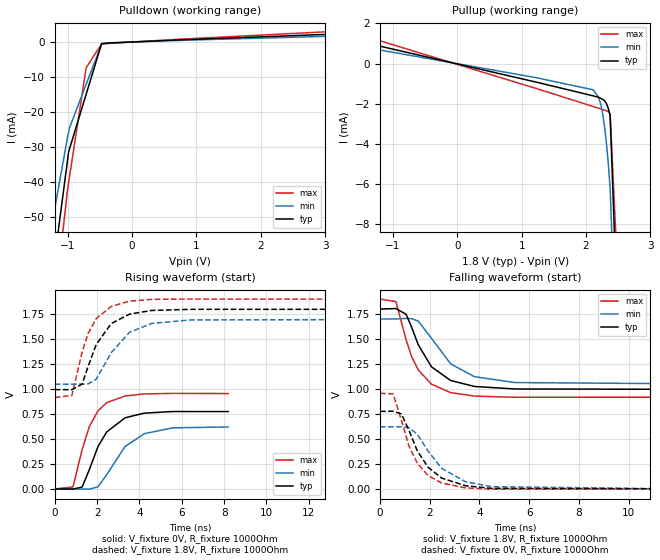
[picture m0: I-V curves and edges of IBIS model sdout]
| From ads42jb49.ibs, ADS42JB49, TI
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|   sdout Model
[Model]   sdout
Model_type   Output
Polarity   Non-Inverting
Vmeas = 0.9
Vref = 1.8
Cref = 2pF
Rref = 2000
|   typ   min   max
|   (nom PVT)   (fast PVT)   (slow PVT)
 C_comp   1.252e-12   1.204e-12   1.298e-12
| Where nom  PVT is Nominal Process, 1.8V, 25C
|   Fast PVT is Strong Process,  1.9V, -40C
|   Slow PVT is Weak Process,   1.7V, 125C
[Voltage Range]   1.8   1.7   1.9
|Junction Temperature
[Temperature Range]   25   125   -40
[Pullup Reference]   1.8   1.7   1.9
[Pulldown Reference]   0   0   0
[Power Clamp Reference]   1.8   1.7   1.9
[GND Clamp Reference]   0   0   0
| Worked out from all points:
|   slope of the pulldown table from 0 to 0.27 V, typ, clamps not added: 1.22 kohm
|   slope of the pullup table from 0 to 0.27 V, typ, clamps not added: 1.33 kohm
|   falling waveform, V_fixture 1.8V, R_fixture 1000Ohm: 20-80 % time 1.11ns typ, 1.34ns min, 925ps max; typ from 1.8 V to 0.996 V
|   rising waveform, V_fixture 0V, R_fixture 1000Ohm: 20-80 % time 1.09ns typ, 1.32ns min, 899ps max; typ from 0 V to 0.775 V
|   rising waveform, V_fixture 1.8V, R_fixture 1000Ohm: 20-80 % time 1.1ns typ, 1.34ns min, 920ps max; typ from 0.995 V to 1.8 V
|   falling waveform, V_fixture 0V, R_fixture 1000Ohm: 20-80 % time 1.08ns typ, 1.29ns min, 908ps max; typ from 0.775 V to 0 V
[Pulldown]
|   Voltage   I(typ)   I(min)   I(max)
-1.8V     -820.6mA   -109.5mA   -1.727A
-1.49V    -102.3mA   -77.5mA    -123.3mA
-1.003V   -34.04mA   -27.36mA   -42.48mA
-984.6mV  -31.42mA   -25.8mA    -40.18mA
-967.3mV  -30.38mA   -24.39mA   -38.1mA
-712.5mV  -14.94mA   -12.12mA   -7.361mA
-472.6mV  -460.4uA   -567.4uA   -540uA
-336.6mV  -280.2uA   -231.3uA   -366.5uA
739.5mV   602.2uA    464.9uA    796uA
3.6V      2.577mA    1.918mA    3.469mA
[Pullup]
|   Voltage   I(typ)   I(min)   I(max)
-1.8V     1.309mA    1.016mA    1.719mA
1.226V    -926.6uA   -706.4uA   -1.243mA
2.113V    -1.613mA   -1.312mA   -2.146mA
2.196V    -1.684mA   -1.696mA   -2.231mA
2.229V    -1.736mA   -2.037mA   -2.264mA
2.259V    -1.788mA   -2.522mA   -2.295mA
2.288V    -1.858mA   -3.157mA   -2.325mA
2.317V    -1.997mA   -3.98mA    -2.357mA
2.344V    -2.227mA   -4.928mA   -2.393mA
2.374V    -2.592mA   -6.201mA   -2.51mA
2.825V    -42.06mA   -45.94mA   -33.2mA
3.6V      -821.5mA   -133.2mA   -867.4mA
[Ramp]
R_load = 1000
|   typ   min   max
dV/dt_r   0.464962/1.08205e-09   0.372481/1.31233e-09   0.573216/8.98731e-10
dV/dt_f   0.482648/1.10643e-09   0.39039/1.33187e-09   0.589514/9.24201e-10
[Falling Waveform]
V_fixture = 1.8V
V_fixture_min = 1.7V
V_fixture_max = 1.9V
R_fixture = 1000Ohm
|   Time   V(typ)   V(min)   V(max)
0s        1.8V       1.7V       1.9V
640ps     1.805V     1.701V     1.875V
1.05ns    1.748V     1.706V     1.493V
1.27ns    1.62V      1.704V     1.326V
1.54ns    1.442V     1.679V     1.191V
2.07ns    1.222V     1.508V     1.048V
2.84ns    1.085V     1.252V     963.5mV
3.8ns     1.025V     1.123V     928.5mV
5.44ns    999.9mV    1.064V     917.2mV
14ns      995.6mV    1.049V     917.5mV
[Rising Waveform]
V_fixture = 0V
V_fixture_min = 0V
V_fixture_max = 0V
R_fixture = 1000Ohm
|   Time   V(typ)   V(min)   V(max)
0s        12.68nV    63.11nV    11.15nV
860ps     -948uV     67.35uV    19.74mV
1.29ns    18.57mV    -738.9uV   392.3mV
1.63ns    191.8mV    -2.055mV   623.1mV
2.04ns    423.5mV    21.38mV    781.8mV
2.45ns    570.2mV    141.8mV    864.2mV
3.32ns    712.7mV    424.7mV    931.4mV
4.23ns    759.6mV    554mV      951.9mV
5.58ns    775.5mV    612.2mV    957.3mV
8.2ns     774.9mV    620.8mV    955.4mV
[Rising Waveform]
V_fixture = 1.8V
V_fixture_min = 1.7V
V_fixture_max = 1.9V
R_fixture = 1000Ohm
|   Time   V(typ)   V(min)   V(max)
0s        995.1mV    1.049V     916mV
810ps     994.7mV    1.049V     937mV
1.29ns    1.05V      1.049V     1.37V
1.58ns    1.23V      1.052V     1.56V
1.96ns    1.448V     1.1V       1.707V
2.67ns    1.657V     1.366V     1.829V
3.53ns    1.751V     1.569V     1.881V
4.58ns    1.788V     1.658V     1.899V
6.39ns    1.799V     1.693V     1.902V
24ns      1.8V       1.7V       1.9V
[Falling Waveform]
V_fixture = 0V
V_fixture_min = 0V
V_fixture_max = 0V
R_fixture = 1000Ohm
|   Time   V(typ)   V(min)   V(max)
0s        775.4mV    620.8mV    956.7mV
530ps     777.5mV    621.3mV    951mV
860ps     750.2mV    622.5mV    687.3mV
1.17ns    583mV      613.2mV    426.4mV
1.5ns     381.2mV    547.6mV    256.7mV
1.93ns    217.2mV    379.7mV    134.6mV
2.48ns    108.1mV    205.3mV    58.32mV
3.45ns    30.66mV    70.31mV    9.384mV
4.5ns     4.733mV    21.87mV    -2.997mV
12ns      12.67nV    63.11nV    11.14nV
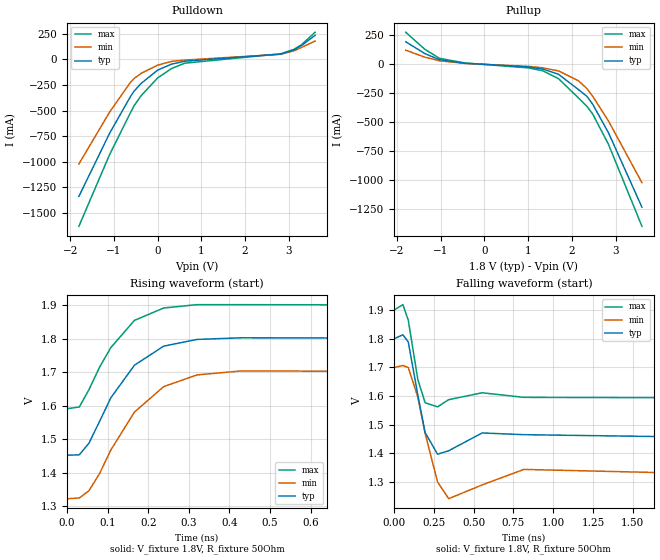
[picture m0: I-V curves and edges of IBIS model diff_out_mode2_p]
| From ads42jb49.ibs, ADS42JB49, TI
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|   diff_out_mode2 Model
[Model]   diff_out_mode2_p
Model_type   Output
Polarity   Non-Inverting
Vmeas = 1.6385
Vref = 1.8
Cref = 0.5pF
Rref = 50
|   typ   min   max
|   (nom PVT)   (fast PVT)   (slow PVT)
C_comp   2.700e-12   2.333e-12   2.765e-12
[Model spec]
|subparameter   typ   min   max
Vmeas   1.6385   1.5288   1.7489
| Where nom  PVT is Nominal Process, 1.8V, 25C
|   Fast PVT is Strong Process,  1.9V, -40C
|   Slow PVT is Weak Process,   1.7V, 125C
[Voltage Range]   1.8   1.7   1.9
|Junction Temperature
[Temperature Range]   25   125   -40
[Pullup Reference]   1.8   1.7   1.9
[Pulldown Reference]   0   0   0
[Power Clamp Reference]   1.8   1.7   1.9
[GND Clamp Reference]   0   0   0
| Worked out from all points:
|   slope of the pulldown table from 0 to 0.27 V, typ, clamps not added: 5.1 ohm
|   slope of the pullup table from 0 to 0.27 V, typ, clamps not added: 49.4 ohm
|   falling waveform, V_fixture 1.8V, R_fixture 50Ohm: 20-80 % time 61.3ps typ, 83.6ps min, 52.9ps max; typ from 1.8 V to 1.45 V
|   rising waveform, V_fixture 1.8V, R_fixture 50Ohm: 20-80 % time 105ps typ, 119ps min, 94.6ps max; typ from 1.45 V to 1.8 V
[Pulldown]
|   Voltage   I(typ)   I(min)   I(max)
-1.8V     -1.338A    -1.021A    -1.63A
-1.096V   -720.2mA   -513.5mA   -928.1mA
-621mV    -362.9mA   -223.5mA   -521mA
-538.2mV  -309.8mA   -186.7mA   -452.7mA
-373.1mV  -233.2mA   -135.2mA   -352.3mA
300uV     -104.8mA   -56.28mA   -180.9mA
316.5mV   -46.52mA   -19.48mA   -89.83mA
621mV     -17.49mA   -6.372mA   -36.72mA
2.819V    52.52mA    50.13mA    54.58mA
3.119V    92.54mA    84.19mA    98.38mA
3.29V     134.9mA    116.7mA    144.1mA
3.6V      235.3mA    179mA      264.9mA
[Pullup]
|   Voltage   I(typ)   I(min)   I(max)
-1.8V     194.6mA    122.1mA    276.8mA
-1.361V   92.3mA     61.21mA    128.8mA
-1.027V   39.25mA    30.36mA    51.49mA
-450mV    9.33mA     7.837mA    11.76mA
1.005V    -22.89mA   -18.07mA   -31.05mA
1.333V    -40.83mA   -30.34mA   -55.62mA
1.694V    -86.52mA   -57.23mA   -124.6mA
2.154V    -219.9mA   -143.9mA   -292.4mA
2.342V    -276.7mA   -210mA     -363.3mA
2.475V    -346mA     -276.7mA   -430.4mA
2.834V    -590.9mA   -489.4mA   -690.6mA
3.6V      -1.235A    -1.023A    -1.4A
[Ramp]
R_load = 50
|   typ   min   max
dV/dt_r   0.0958658/5.93092e-11   0.126182/7.52687e-11  0.0776585/4.97499e-11
dV/dt_f   0.208176/6.1056e-11   0.226063/8.32221e-11   0.184056/5.25283e-11
[Falling Waveform]
V_fixture = 1.8V
V_fixture_min = 1.7V
V_fixture_max = 1.9V
R_fixture = 50Ohm
|   Time   V(typ)   V(min)   V(max)
0s        1.799V     1.699V     1.899V
56ps      1.813V     1.706V     1.918V
90ps      1.788V     1.699V     1.864V
150ps     1.603V     1.596V     1.657V
196ps     1.472V     1.469V     1.576V
274ps     1.397V     1.3V       1.562V
344ps     1.409V     1.242V     1.587V
554ps     1.471V     1.29V      1.611V
816ps     1.465V     1.344V     1.595V
2.498ns   1.452V     1.322V     1.593V
[Rising Waveform]
V_fixture = 1.8V
V_fixture_min = 1.7V
V_fixture_max = 1.9V
R_fixture = 50Ohm
|   Time   V(typ)   V(min)   V(max)
0s        1.452V     1.322V     1.591V
30ps      1.453V     1.324V     1.596V
54ps      1.488V     1.346V     1.648V
80ps      1.553V     1.397V     1.715V
108ps     1.624V     1.468V     1.774V
166ps     1.721V     1.581V     1.855V
238ps     1.778V     1.657V     1.892V
320ps     1.798V     1.692V     1.902V
430ps     1.803V     1.704V     1.902V
1.8ns     1.799V     1.698V     1.899V
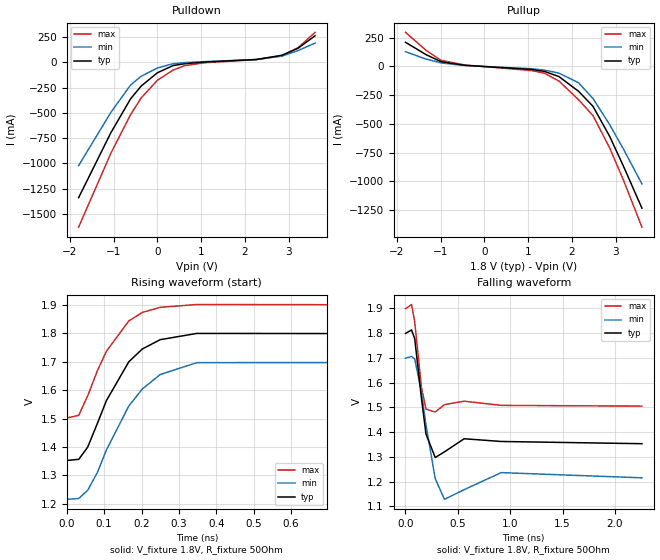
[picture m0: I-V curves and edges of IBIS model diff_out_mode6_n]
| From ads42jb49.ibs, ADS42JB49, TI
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[Model]   diff_out_mode6_n
Model_type   Output
Polarity   Non-Inverting
Vmeas = 1.589
Vref = 1.8
Cref = 0.5pF
Rref = 50
|   typ   min   max
|   (nom PVT)   (fast PVT)   (slow PVT)
C_comp   2.834e-12   2.356e-12   2.851e-12
[Model spec]
|subparameter   typ   min   max
Vmeas   1.589   1.49   1.7074
| Where nom  PVT is Nominal Process, 1.8V, 25C
|   Fast PVT is Strong Process,  1.9V, -40C
|   Slow PVT is Weak Process,   1.7V, 125C
[Voltage Range]   1.8   1.7   1.9
|Junction Temperature
[Temperature Range]   25   125   -40
[Pullup Reference]   1.8   1.7   1.9
[Pulldown Reference]   0   0   0
[Power Clamp Reference]   1.8   1.7   1.9
[GND Clamp Reference]   0   0   0
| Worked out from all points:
|   slope of the pulldown table from 0 to 0.27 V, typ, clamps not added: 4.94 ohm
|   slope of the pullup table from 0 to 0.27 V, typ, clamps not added: 49.4 ohm
|   falling waveform, V_fixture 1.8V, R_fixture 50Ohm: 20-80 % time 67.1ps typ, 95.6ps min, 56.3ps max; typ from 1.8 V to 1.35 V
|   rising waveform, V_fixture 1.8V, R_fixture 50Ohm: 20-80 % time 102ps typ, 118ps min, 91.1ps max; typ from 1.35 V to 1.8 V
[Pulldown]
|   Voltage   I(typ)   I(min)   I(max)
-1.8V     -1.341A    -1.023A    -1.633A
-1.063V   -697.3mA   -495.9mA   -900.2mA
-613.8mV  -362.2mA   -224.7mA   -518.5mA
-373.1mV  -235.8mA   -138.1mA   -353.7mA
20.08fV   -102.9mA   -55.72mA   -177.1mA
358.2mV   -31.82mA   -13.52mA   -76.66mA
621mV     -13.42mA   -2.427mA   -32.54mA
1.082V    3.463mA    7.44mA     -3.434mA
2.252V    27.83mA    28.39mA    27.17mA
2.842V    70.11mA    61.5mA     65.03mA
3.213V    140.7mA    117mA      145.1mA
3.6V      263.4mA    191mA      297.7mA
[Pullup]
|   Voltage   I(typ)   I(min)   I(max)
-1.8V     210.2mA    128.1mA    296.7mA
-1.323V   100.9mA    62.84mA    137.7mA
-986.8mV  40.99mA    30.49mA    52.6mA
-450mV    9.747mA    7.957mA    12.52mA
1.082V    -26.39mA   -20.41mA   -36.01mA
1.374V    -43.31mA   -32.15mA   -58.84mA
1.705V    -88.58mA   -58.29mA   -127.7mA
2.154V    -217mA     -142.8mA   -290.2mA
2.483V    -347.4mA   -279.5mA   -428.4mA
2.865V    -610.5mA   -507.9mA   -710.8mA
3.182V    -871.6mA   -722.3mA   -993.5mA
3.6V      -1.234A    -1.023A    -1.399A
[Ramp]
R_load = 50
|   typ   min   max
dV/dt_r   0.112303/5.91752e-11   0.147577/7.37215e-11  0.0911225/4.77241e-11
dV/dt_f   0.267621/6.70703e-11   0.290297/9.55783e-11   0.236283/5.62373e-11
[Falling Waveform]
V_fixture = 1.8V
V_fixture_min = 1.7V
V_fixture_max = 1.9V
R_fixture = 50Ohm
|   Time   V(typ)   V(min)   V(max)
0s        1.799V     1.699V     1.899V
58ps      1.813V     1.706V     1.916V
88ps      1.778V     1.696V     1.847V
152ps     1.539V     1.564V     1.582V
196ps     1.392V     1.429V     1.493V
284ps     1.297V     1.212V     1.481V
372ps     1.32V      1.128V     1.511V
560ps     1.373V     1.167V     1.525V
914ps     1.362V     1.236V     1.508V
2.258ns   1.353V     1.215V     1.505V
[Rising Waveform]
V_fixture = 1.8V
V_fixture_min = 1.7V
V_fixture_max = 1.9V
R_fixture = 50Ohm
|   Time   V(typ)   V(min)   V(max)
0s        1.352V     1.215V     1.502V
32ps      1.356V     1.218V     1.511V
56ps      1.399V     1.247V     1.58V
82ps      1.483V     1.31V      1.669V
106ps     1.563V     1.389V     1.737V
166ps     1.7V       1.544V     1.844V
202ps     1.745V     1.604V     1.874V
250ps     1.778V     1.655V     1.892V
348ps     1.8V       1.697V     1.902V
2ns       1.798V     1.698V     1.899V
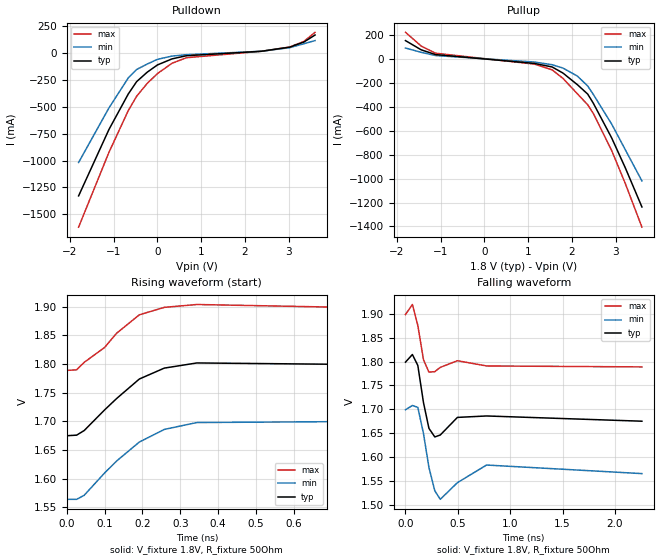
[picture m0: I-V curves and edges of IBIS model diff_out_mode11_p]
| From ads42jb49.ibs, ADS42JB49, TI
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|   diff_out_mode11 Model
[Model]   diff_out_mode11_p
Model_type   Output
Polarity   Non-Inverting
Vmeas = 1.741
Vref = 1.8
Cref = 0.5pF
Rref = 50
|   typ   min   max
|   (nom PVT)   (fast PVT)   (slow PVT)
C_comp   2.464e-12   2.327e-12   2.521e-12
[Model spec]
|subparameter   typ   min   max
Vmeas   1.741   1.641   1.839
| Where nom  PVT is Nominal Process, 1.8V, 25C
|   Fast PVT is Strong Process,  1.9V, -40C
|   Slow PVT is Weak Process,   1.7V, 125C
[Voltage Range]   1.8   1.7   1.9
|Junction Temperature
[Temperature Range]   25   125   -40
[Pullup Reference]   1.8   1.7   1.9
[Pulldown Reference]   0   0   0
[Power Clamp Reference]   1.8   1.7   1.9
[GND Clamp Reference]   0   0   0
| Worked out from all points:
|   slope of the pulldown table from 0 to 0.27 V, typ, clamps not added: 5.59 ohm
|   slope of the pullup table from 0 to 0.27 V, typ, clamps not added: 49.4 ohm
|   falling waveform, V_fixture 1.8V, R_fixture 50Ohm: 20-80 % time 51.5ps typ, 60.1ps min, 48.7ps max; typ from 1.8 V to 1.68 V
|   rising waveform, V_fixture 1.8V, R_fixture 50Ohm: 20-80 % time 127ps typ, 138ps min, 107ps max; typ from 1.68 V to 1.8 V
[Pulldown]
|   Voltage   I(typ)   I(min)   I(max)
-1.8V     -1.329A    -1.018A    -1.62A
-1.107V   -710.9mA   -510.4mA   -923.6mA
-665mV    -380mA     -230.6mA   -534.5mA
-473.4mV  -264.9mA   -152.2mA   -400.9mA
-231.8mV  -177.2mA   -101.6mA   -281.5mA
11.97fV   -110.1mA   -58.1mA    -190.8mA
334.4mV   -53.56mA   -27.52mA   -94.21mA
665mV     -24.29mA   -14.77mA   -42.78mA
2.378V    17.15mA    17.33mA    17.39mA
3.023V    55.88mA    50.66mA    56.97mA
3.344V    103mA      87.29mA    108.9mA
3.6V      168.4mA    116.5mA    193.5mA
[Pullup]
|   Voltage   I(typ)   I(min)   I(max)
-1.8V     156.3mA    94.21mA    225.7mA
-1.44V    78.89mA    58.06mA    110.3mA
-1.113V   39.32mA    31.17mA    50.75mA
1.146V    -34.76mA   -23.05mA   -40.73mA
1.55V     -64.55mA   -45.65mA   -88.85mA
1.797V    -115.5mA   -73.87mA   -160.1mA
2.127V    -213.2mA   -140.9mA   -289.5mA
2.362V    -291.7mA   -224mA     -381.2mA
2.491V    -368.8mA   -295.1mA   -453.9mA
2.909V    -658.6mA   -542.8mA   -764.6mA
3.222V    -910.5mA   -758.8mA   -1.042A
3.6V      -1.237A    -1.019A    -1.406A
[Ramp]
R_load = 50
|   typ   min   max
dV/dt_r   0.044958/9.6857e-11   0.057593/1.11307e-10  0.0363552/8.15696e-11
dV/dt_f   0.0743614/5.14554e-11  0.0808168/6.01146e-11   0.065987/4.7678e-11
[Falling Waveform]
V_fixture = 1.8V
V_fixture_min = 1.7V
V_fixture_max = 1.9V
R_fixture = 50Ohm
|   Time   V(typ)   V(min)   V(max)
0s        1.799V     1.699V     1.899V
66ps      1.815V     1.708V     1.92V
118ps     1.792V     1.704V     1.876V
172ps     1.714V     1.649V     1.804V
224ps     1.66V      1.578V     1.778V
280ps     1.642V     1.529V     1.779V
332ps     1.646V     1.511V     1.788V
496ps     1.683V     1.546V     1.802V
774ps     1.686V     1.583V     1.791V
2.258ns   1.675V     1.565V     1.789V
[Rising Waveform]
V_fixture = 1.8V
V_fixture_min = 1.7V
V_fixture_max = 1.9V
R_fixture = 50Ohm
|   Time   V(typ)   V(min)   V(max)
0s        1.675V     1.564V     1.789V
26ps      1.676V     1.564V     1.79V
46ps      1.684V     1.571V     1.803V
100ps     1.72V      1.61V      1.829V
132ps     1.74V      1.631V     1.854V
192ps     1.774V     1.664V     1.886V
258ps     1.793V     1.686V     1.899V
344ps     1.802V     1.698V     1.904V
816ps     1.799V     1.7V       1.898V
2.012ns   1.799V     1.699V     1.899V
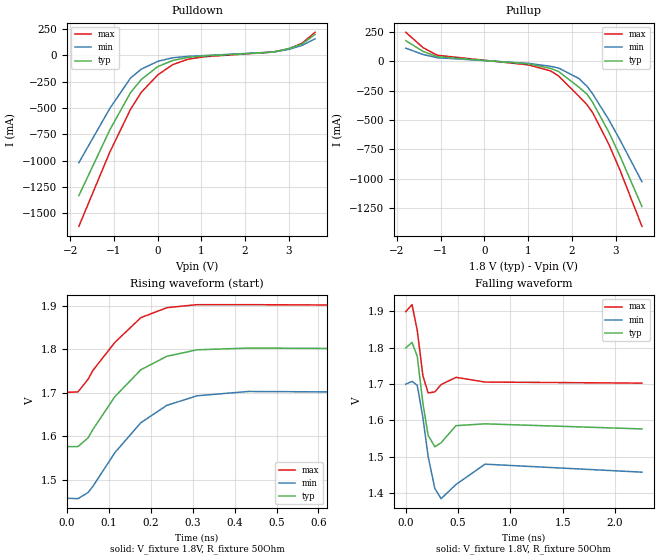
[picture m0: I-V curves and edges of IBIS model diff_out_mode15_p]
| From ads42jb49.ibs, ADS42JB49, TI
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|   diff_out_mode15 Model
[Model]   diff_out_mode15_p
Model_type   Output
Polarity   Non-Inverting
Vmeas = 1.6941
Vref = 1.8
Cref = 0.5pF
Rref = 50
|   typ   min   max
|   (nom PVT)   (fast PVT)   (slow PVT)
C_comp   2.529e-12   2.310e-12   2.646e-12
[Model spec]
Vmeas   1.6941   1.5884   1.8048
| Where nom  PVT is Nominal Process, 1.8V, 25C
|   Fast PVT is Strong Process,  1.9V, -40C
|   Slow PVT is Weak Process,   1.7V, 125C
[Voltage Range]   1.8   1.7   1.9
|Junction Temperature
[Temperature Range]   25   125   -40
[Pullup Reference]   1.8   1.7   1.9
[Pulldown Reference]   0   0   0
[Power Clamp Reference]   1.8   1.7   1.9
[GND Clamp Reference]   0   0   0
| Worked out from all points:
|   slope of the pulldown table from 0 to 0.27 V, typ, clamps not added: 5.3 ohm
|   slope of the pullup table from 0 to 0.27 V, typ, clamps not added: 49.4 ohm
|   falling waveform, V_fixture 1.8V, R_fixture 50Ohm: 20-80 % time 54.2ps typ, 68.7ps min, 48.4ps max; typ from 1.8 V to 1.58 V
|   rising waveform, V_fixture 1.8V, R_fixture 50Ohm: 20-80 % time 113ps typ, 124ps min, 102ps max; typ from 1.58 V to 1.8 V
[Pulldown]
|   Voltage   I(typ)   I(min)   I(max)
-1.8V     -1.333A    -1.02A     -1.625A
-1.095V   -710.1mA   -505.7mA   -921.4mA
-621mV    -355.5mA   -216.2mA   -514.1mA
-373.1mV  -229mA     -130.8mA   -350.7mA
9mV       -105.3mA   -55.96mA   -183.5mA
345.1mV   -48.66mA   -22.73mA   -88.09mA
698.5mV   -18.44mA   -8.995mA   -35.8mA
1.082V    -5.548mA   -1.497mA   -12.48mA
2.638V    31.15mA    31.42mA    31.98mA
2.988V    64.07mA    55.75mA    60.93mA
3.3V      107.5mA    94.68mA    114.9mA
3.6V      199.2mA    157.3mA    219.6mA
[Pullup]
|   Voltage   I(typ)   I(min)   I(max)
-1.8V     175mA      110.9mA    246.1mA
-1.404V   83.26mA    57.23mA    115.3mA
-1.08V    38.66mA    29.99mA    50.84mA
1.005V    -22.92mA   -18.08mA   -31.11mA
1.512V    -60.79mA   -43.15mA   -82.11mA
1.694V    -87.05mA   -57.74mA   -125.3mA
2.154V    -219mA     -145.7mA   -295.7mA
2.344V    -279.6mA   -212.5mA   -369.6mA
2.472V    -348.5mA   -276.6mA   -436mA
2.836V    -597.9mA   -492.7mA   -700.3mA
3.094V    -802.2mA   -665.9mA   -921.5mA
3.6V      -1.235A    -1.024A    -1.403A
[Ramp]
R_load = 50
|   typ   min   max
dV/dt_r   0.0707759/6.96462e-11  0.0921237/8.64583e-11  0.0572391/6.35115e-11
dV/dt_f   0.133871/5.40771e-11   0.145435/6.87116e-11   0.118573/4.75964e-11
[Falling Waveform]
V_fixture = 1.8V
V_fixture_min = 1.7V
V_fixture_max = 1.9V
R_fixture = 50Ohm
|   Time   V(typ)   V(min)   V(max)
0s        1.799V     1.699V     1.899V
60ps      1.814V     1.707V     1.918V
110ps     1.776V     1.696V     1.847V
164ps     1.646V     1.607V     1.722V
214ps     1.558V     1.5V       1.675V
278ps     1.527V     1.412V     1.678V
338ps     1.538V     1.384V     1.698V
480ps     1.585V     1.423V     1.718V
758ps     1.59V      1.479V     1.705V
2.258ns   1.576V     1.457V     1.702V
[Rising Waveform]
V_fixture = 1.8V
V_fixture_min = 1.7V
V_fixture_max = 1.9V
R_fixture = 50Ohm
|   Time   V(typ)   V(min)   V(max)
0s        1.576V     1.457V     1.701V
26ps      1.576V     1.456V     1.702V
50ps      1.596V     1.47V      1.731V
62ps      1.616V     1.485V     1.752V
114ps     1.691V     1.562V     1.816V
176ps     1.753V     1.631V     1.873V
238ps     1.784V     1.671V     1.896V
310ps     1.799V     1.693V     1.903V
432ps     1.803V     1.703V     1.903V
1.416ns   1.799V     1.698V     1.899V
